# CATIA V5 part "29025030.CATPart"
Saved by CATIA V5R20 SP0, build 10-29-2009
Part number: 29025030
Definition: NONE
Nomenclature: 29025030
Source: Unknown
Description: 29025030
Bounding box of the stored display mesh (mm): x -15 to 44.548, y -26.5 to 61.048, z -16.5 to 16.5
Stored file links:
  C:\Users\Utente\Desktop\IO LAVORO\3D X SITO CF\X SITO\PLASTICA\RF1\29025030.CATPart

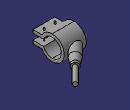
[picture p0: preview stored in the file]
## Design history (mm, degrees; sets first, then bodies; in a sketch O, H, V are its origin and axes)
Body1 "29025030" (main body)
  Solid1: solid without history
